One B-rep face of a CAD part: STEP entity #4136.
In plain terms, the planar face has unit normal (0, 1, 0).
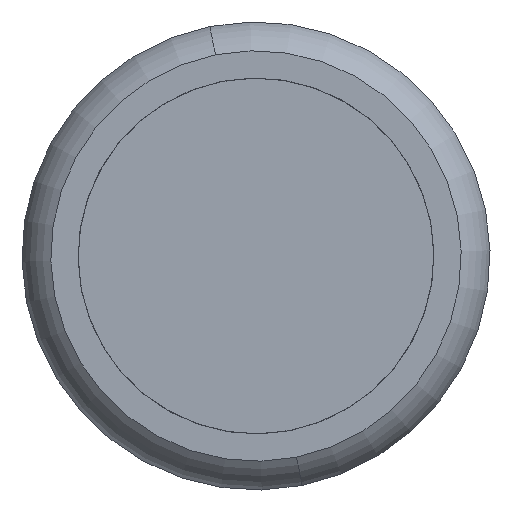
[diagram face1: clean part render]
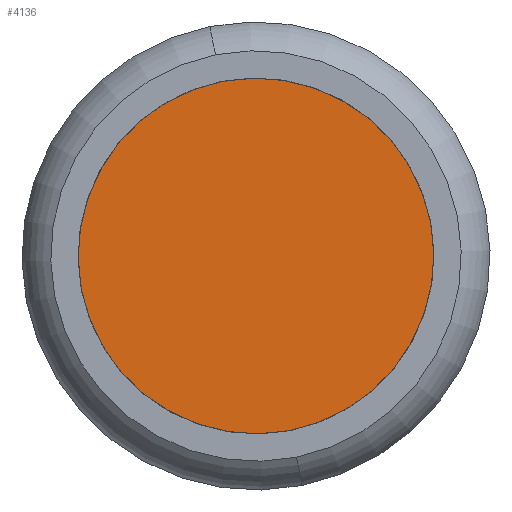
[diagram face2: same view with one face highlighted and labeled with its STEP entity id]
Its self-contained STEP definition (entity closure, numbers rounded to 3 decimals):
#13 = DIRECTION ( 'NONE',  ( 0., 0., -1. ) ) ;
#319 = CARTESIAN_POINT ( 'NONE',  ( 0., 2.45, 1.9 ) ) ;
#422 = DIRECTION ( 'NONE',  ( 0., -1., 0. ) ) ;
#1054 = EDGE_CURVE ( 'NONE', #7042, #2438, #9388, .T. ) ;
#1424 = DIRECTION ( 'NONE',  ( 0., 0., -1. ) ) ;
#1506 = ORIENTED_EDGE ( 'NONE', *, *, #10131, .F. ) ;
#2314 = AXIS2_PLACEMENT_3D ( 'NONE', #3970, #422, #1424 ) ;
#2438 = VERTEX_POINT ( 'NONE', #319 ) ;
#3777 = AXIS2_PLACEMENT_3D ( 'NONE', #9222, #5781, #8397 ) ;
#3857 = PLANE ( 'NONE',  #2314 ) ;
#3970 = CARTESIAN_POINT ( 'NONE',  ( -2.192, 2.45, 10. ) ) ;
#4127 = CIRCLE ( 'NONE', #3777, 1.9 ) ;
#4136 = ADVANCED_FACE ( 'NONE', ( #6359 ), #3857, .F. ) ;
#5321 = CARTESIAN_POINT ( 'NONE',  ( 0., 2.45, -1.9 ) ) ;
#5781 = DIRECTION ( 'NONE',  ( 0., -1., 0. ) ) ;
#6322 = ORIENTED_EDGE ( 'NONE', *, *, #1054, .F. ) ;
#6359 = FACE_OUTER_BOUND ( 'NONE', #7881, .T. ) ;
#6663 = DIRECTION ( 'NONE',  ( 0., -1., 0. ) ) ;
#7042 = VERTEX_POINT ( 'NONE', #5321 ) ;
#7881 = EDGE_LOOP ( 'NONE', ( #1506, #6322 ) ) ;
#8397 = DIRECTION ( 'NONE',  ( 0., 0., -1. ) ) ;
#8666 = AXIS2_PLACEMENT_3D ( 'NONE', #9282, #6663, #13 ) ;
#9222 = CARTESIAN_POINT ( 'NONE',  ( 0., 2.45, 0. ) ) ;
#9282 = CARTESIAN_POINT ( 'NONE',  ( 0., 2.45, 0. ) ) ;
#9388 = CIRCLE ( 'NONE', #8666, 1.9 ) ;
#10131 = EDGE_CURVE ( 'NONE', #2438, #7042, #4127, .T. ) ;
